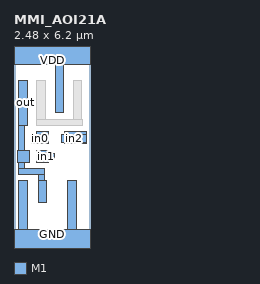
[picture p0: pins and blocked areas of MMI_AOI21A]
MACRO MMI_AOI21A
	CLASS CORE ;
	FOREIGN MMI_AOI21A 0 0 ;
	SIZE 2.48 BY 6.2 ;
	SYMMETRY X Y ;
	SITE CORE1 ;
	PIN out
		DIRECTION output ;
		USE SIGNAL ;
		PORT
			LAYER M1 ;
			RECT 0.16 3.815 0.44 5.285 ;
			LAYER M1 ;
			RECT 0.16 2.98 0.355 3.815 ;
			LAYER M1 ;
			RECT 0.12 2.6 0.5 2.98 ;
			LAYER M1 ;
			RECT 0.16 2.395 0.355 2.6 ;
			LAYER M1 ;
			RECT 0.16 2.2 0.985 2.395 ;
			LAYER M1 ;
			RECT 0.795 1.995 0.985 2.2 ;
			LAYER M1 ;
			RECT 0.795 1.295 1.075 1.995 ;
		END
		AntennaDiffArea 0.948 ;
	END out
	PIN in1
		DIRECTION input ;
		USE SIGNAL ;
		PORT
			LAYER M1 ;
			RECT 0.74 2.93 1.12 2.98 ;
			LAYER M1 ;
			RECT 0.74 2.885 1.27 2.93 ;
			LAYER M1 ;
			RECT 0.74 2.695 1.33 2.885 ;
			LAYER M1 ;
			RECT 0.74 2.65 1.27 2.695 ;
			LAYER M1 ;
			RECT 0.74 2.6 1.12 2.65 ;
		END
		AntennaGateArea 0.3465 ;
	END in1
	PIN GND
		DIRECTION inout ;
		USE GROUND ;
		PORT
			LAYER M1 ;
			RECT 0.16 0.42 0.44 2 ;
			LAYER M1 ;
			RECT 1.755 0.42 2.035 1.995 ;
			LAYER M1 ;
			RECT 0 -0.42 2.48 0.42 ;
		END
	END GND
	PIN in2
		DIRECTION input ;
		USE SIGNAL ;
		PORT
			LAYER M1 ;
			RECT 1.65 3.515 2.36 3.6 ;
			LAYER M1 ;
			RECT 1.56 3.235 2.36 3.515 ;
			LAYER M1 ;
			RECT 1.65 3.22 2.36 3.235 ;
		END
		AntennaGateArea 0.3465 ;
	END in2
	PIN VDD
		DIRECTION inout ;
		USE POWER ;
		PORT
			LAYER M1 ;
			RECT 0 5.78 2.48 6.62 ;
			LAYER M1 ;
			RECT 1.34 4.225 1.62 5.78 ;
		END
	END VDD
	PIN in0
		DIRECTION input ;
		USE SIGNAL ;
		PORT
			LAYER M1 ;
			RECT 0.74 3.51 1.12 3.6 ;
			LAYER M1 ;
			RECT 0.555 3.23 1.12 3.51 ;
			LAYER M1 ;
			RECT 0.74 3.22 1.12 3.23 ;
		END
		AntennaGateArea 0.28875 ;
	END in0
	OBS
		LAYER M1 ;
		RECT 0.75 4.01 1.03 5.285 ;
		LAYER M1 ;
		RECT 1.93 4.01 2.21 5.285 ;
		LAYER M1 ;
		RECT 0.75 3.815 2.245 4.01 ;
	END
END MMI_AOI21A
